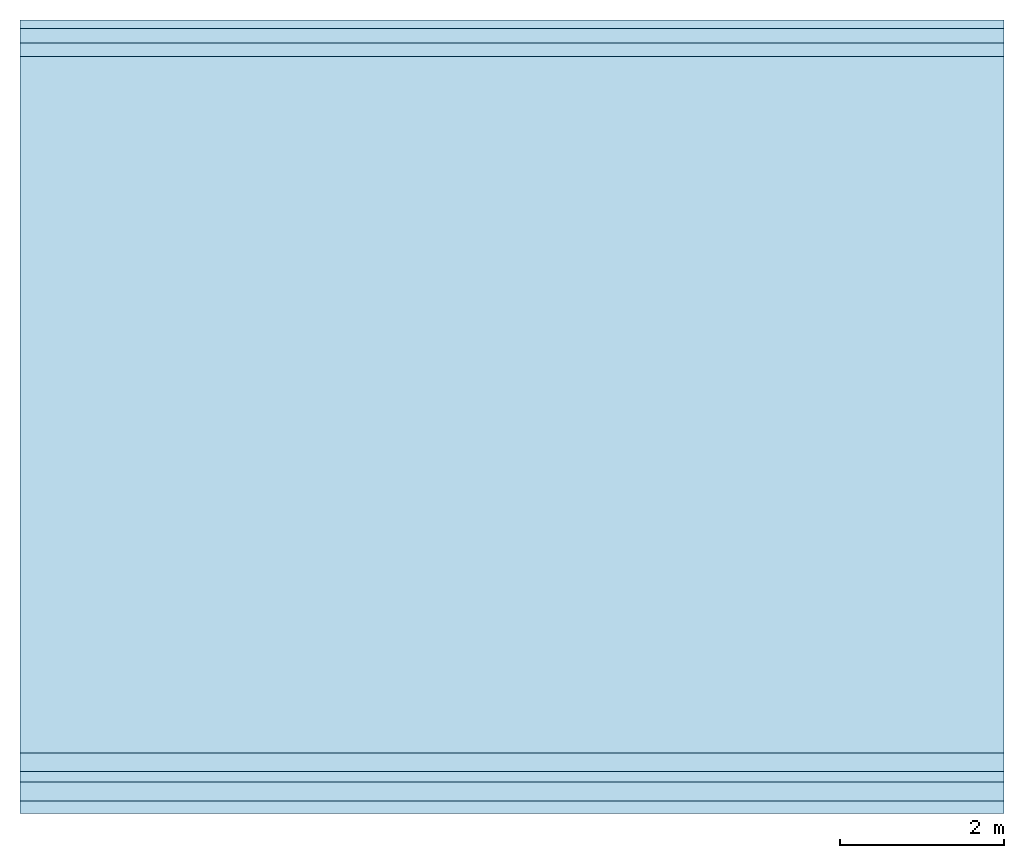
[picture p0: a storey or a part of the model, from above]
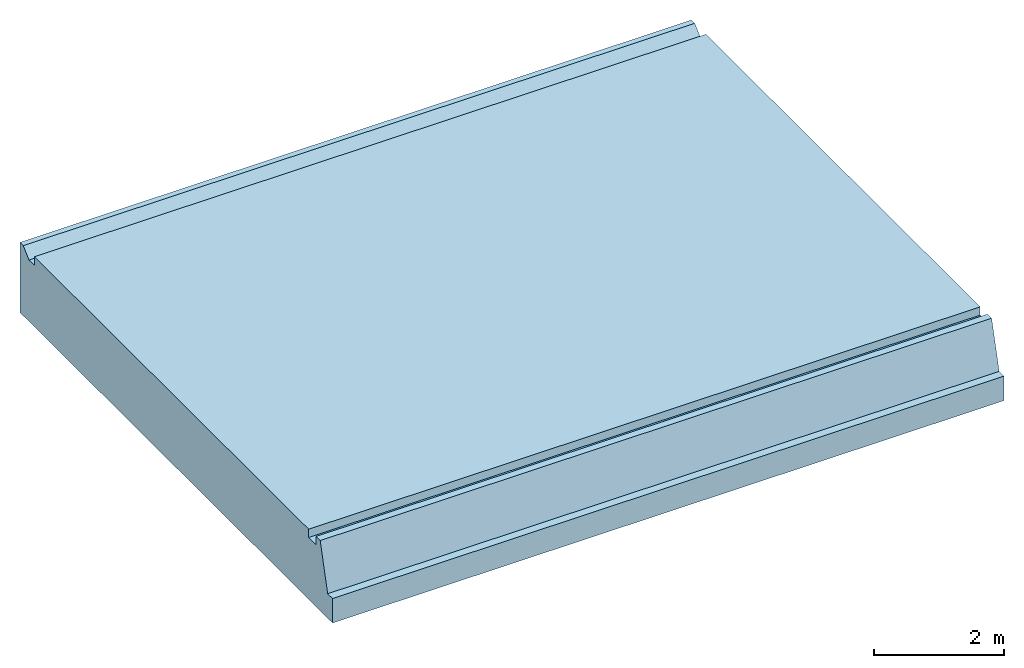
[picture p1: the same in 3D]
Properties of the parts of a building model (IFC2X3)

# File
Description: ViewDefinition [CoordinationView]
File name: VA006-350-202.1 (EDITED).ifc (Edited by Naviate Simple BIM 2022 version 6)
Time: 2026-03-20T14:25:04+01:00
Written by: ODA SDAI 22.12
Made in: Autodesk Revit 23.1.90.15 (ENU) - IFC 23.3.1.0

# IfcProject
LongName: Trondheim Lufthavn Værnes; Phase: TU 2013

# IfcSite, Default
RefLatitude: 59, 54, 57, 601318; RefLongitude: 10, 44, 59, 999999; RefElevation: 0 mm
Identity Data - Workset: Project Info
Text - 01_Modellfil: va006-a-220-1-0001.rvt
Other - RIE, firma: RAMBØLL AS; Project Status: TU 2013; Saksbehandler: MR; Project Address: Skriv adresse her; Category: Project Information; Prosjektansvarlig: TILBUD E203 TETT BYGG; RIV, telefon: +47 7310 6200; RIB, telefon: +47 7289 3750; Project Name: Trondheim Lufthavn Værnes; RIV, firma: MULTICONSULT AS; RIB, firma: NORCONSULT; RIE, telefon: +47 7389 1000
Data - Ideate BIMLink: <?xml version="1.0" encoding="utf-8"?><application version="3"> <links> <link> <name>Casework Types</name> <description></description> <elements>CaseworkTypes</elements> <phase>Fase 2</phase> <phase_filter>None</phase_filter> <properties> <property> <name>Id</name> <lookup_1_type></lookup_1_type> <lookup_1_id></lookup_1_id> <type>BUILT_IN_PARAMETER</type> <id>ID_PARAM</id> </property> <property> <name>Family Name</name> <lookup_1_type></lookup_1_type> <lookup_1_id></lookup_1_id> <type>CALCULATED_PROPERTY</type> <id>FamilyName</id> </property> <property> <name>Type Name</name> <lookup_1_type></lookup_1_type> <lookup_1_id></lookup_1_id> <type>CALCULATED_PROPERTY</type> <id>TypeName</id> </property> </properties> </link> <link> <name>Window Types</name> <description></description> <elements>WindowTypes</elements> <phase>Fase 2</phase> <phase_filter>None</phase_filter> <properties> <property> <name>Id</name> <lookup_1_type></lookup_1_type> <lookup_1_id></lookup_1_id> <type>BUILT_IN_PARAMETER</type> <id>ID_PARAM</id> </property> <property> <name>Family Name</name> <lookup_1_type></lookup_1_type> <lookup_1_id></lookup_1_id> <type>CALCULATED_PROPERTY</type> <id>FamilyName</id> </property> <property> <name>Type Name</name> <lookup_1_type></lookup_1_type> <lookup_1_id></lookup_1_id> <type>CALCULATED_PROPERTY</type> <id>TypeName</id> </property> </properties> </link> <link> <name>Wall Types</name> <description></description> <elements>WallTypes</elements> <phase>Fase 1</phase> <phase_filter>Show Complete</phase_filter> <properties> <property> <name>Id</name> <lookup_1_type></lookup_1_type> <lookup_1_id></lookup_1_id> <type>BUILT_IN_PARAMETER</type> <id>ID_PARAM</id> </property> <property> <name>Family Name</name> <lookup_1_type></lookup_1_type> <lookup_1_id></lookup_1_id> <type>BUILT_IN_PARAMETER</type> <id>SYMBOL_FAMILY_NAME_PARAM</id> </property> <property> <name>Type Name</name> <lookup_1_type></lookup_1_type> <lookup_1_id></lookup_1_id> <type>CALCULATED_PROPERTY</type> <id>TypeName</id> </property> </properties> </link> <link> <name>Structural Framing Types</name> <description></description> <elements>StructuralFramingTypes</elements> <phase>Fase 2</phase> <phase_filter>None</phase_filter> <properties> <property> <name>Id</name> <lookup_1_type></lookup_1_type> <lookup_1_id></lookup_1_id> <type>BUILT_IN_PARAMETER</type> <id>ID_PARAM</id> </property> <property> <name>Family Name</name> <lookup_1_type></lookup_1_type> <lookup_1_id></lookup_1_id> <type>CALCULATED_PROPERTY</type> <id>FamilyName</id> </property> <property> <name>Type Name</name> <lookup_1_type></lookup_1_type> <lookup_1_id></lookup_1_id> <type>CALCULATED_PROPERTY</type> <id>TypeName</id> </property> </properties> </link> <link> <name>Structural Foundation Types</name> <description></description> <elements>StructuralFoundationTypes</elements> <phase>Fase 2</phase> <phase_filter>None</phase_filter> <properties> <property> <name>Id</name> <lookup_1_type></lookup_1_type> <lookup_1_id></lookup_1_id> <type>BUILT_IN_PARAMETER</type> <id>ID_PARAM</id> </property> <property> <name>Family Name</name> <lookup_1_type></lookup_1_type> <lookup_1_id></lookup_1_id> <type>CALCULATED_PROPERTY</type> <id>FamilyName</id> </property> <property> <name>Type Name</name> <lookup_1_type></lookup_1_type> <lookup_1_id></lookup_1_id> <type>CALCULATED_PROPERTY</type> <id>TypeName</id> </property> </properties> </link> <link> <name>Structural Column Types</name> <description></description> <elements>StructuralColumnTypes</elements> <phase>Fase 2</phase> <phase_filter>None</phase_filter> <properties> <property> <name>Id</name> <lookup_1_type></lookup_1_type> <lookup_1_id></lookup_1_id> <type>BUILT_IN_PARAMETER</type> <id>ID_PARAM</id> </property> <property> <name>Family Name</name> <lookup_1_type></lookup_1_type> <lookup_1_id></lookup_1_id> <type>CALCULATED_PROPERTY</type> <id>FamilyName</id> </property> <property> <name>Type Name</name> <lookup_1_type></lookup_1_type> <lookup_1_id></lookup_1_id> <type>CALCULATED_PROPERTY</type> <id>TypeName</id> </property> </properties> </link> <link> <name>Stair Types</name> <description></description> <elements>StairTypes</elements> <phase>Fase 2</phase> <phase_filter>None</phase_filter> <properties> <property> <name>Id</name> <lookup_1_type></lookup_1_type> <lookup_1_id></lookup_1_id> <type>BUILT_IN_PARAMETER</type> <id>ID_PARAM</id> </property> <property> <name>Family Name</name> <lookup_1_type></lookup_1_type> <lookup_1_id></lookup_1_id> <type>BUILT_IN_PARAMETER</type> <id>ALL_MODEL_FAMILY_NAME</id> </property> <property> <name>Type Name</name> <lookup_1_type></lookup_1_type> <lookup_1_id></lookup_1_id> <type>CALCULATED_PROPERTY</type> <id>TypeName</id> </property> </properties> </link> <link> <name>Specialty Equipment Types</name> <description></description> <elements>SpecialtyEquipmentTypes</elements> <phase>Fase 2</phase> <phase_filter>None</phase_filter> <properties> <property> <name>Id</name> <lookup_1_type></lookup_1_type> <lookup_1_id></lookup_1_id> <type>BUILT_IN_PARAMETER</type> <id>ID_PARAM</id> </property> <property> <name>Family Name</name> <lookup_1_type></lookup_1_type> <lookup_1_id></lookup_1_id> <type>CALCULATED_PROPERTY</type> <id>FamilyName</id> </property> <property> <name>Type Name</name> <lookup_1_type></lookup_1_type> <lookup_1_id></lookup_1_id> <type>CALCULATED_PROPERTY</type> <id>TypeName</id> </property> </properties> </link> <link> <name>Roof Types</name> <description></description> <elements>RoofTypes</elements> <phase>Fase 2</phase> <phase_filter>None</phase_filter> <properties> <property> <name>Id</name> <lookup_1_type></lookup_1_type> <lookup_1_id></lookup_1_id> <type>BUILT_IN_PARAMETER</type> <id>ID_PARAM</id> </property> <property> <name>Family Name</name> <lookup_1_type></lookup_1_type> <lookup_1_id></lookup_1_id> <type>BUILT_IN_PARAMETER</type> <id>ALL_MODEL_FAMILY_NAME</id> </property> <property> <name>Type Name</name> <lookup_1_type></lookup_1_type> <lookup_1_id></lookup_1_id> <type>CALCULATED_PROPERTY</type> <id>TypeName</id> </property> </properties> </link> <link> <name>Ramp Types</name> <description></description> <elements>RampTypes</elements> <phase>Fase 2</phase> <phase_filter>None</phase_filter> <properties> <property> <name>Id</name> <lookup_1_type></lookup_1_type> <lookup_1_id></lookup_1_id> <type>BUILT_IN_PARAMETER</type> <id>ID_PARAM</id> </property> <property> <name>Family Name</name> <lookup_1_type></lookup_1_type> <lookup_1_id></lookup_1_id> <type>BUILT_IN_PARAMETER</type> <id>ALL_MODEL_FAMILY_NAME</id> </property> <property> <name>Type Name</name> <lookup_1_type></lookup_1_type> <lookup_1_id></lookup_1_id> <type>CALCULATED_PROPERTY</type> <id>TypeName</id> </property> </properties> </link> <link> <name>Railing Types</name> <description></description> <elements>RailingTypes</elements> <phase>Fase 2</phase> <phase_filter>None</phase_filter> <properties> <property> <name>Id</name> <lookup_1_type></lookup_1_type> <lookup_1_id></lookup_1_id> <type>BUILT_IN_PARAMETER</type> <id>ID_PARAM</id> </property> <property> <name>Family Name</name> <lookup_1_type></lookup_1_type> <lookup_1_id></lookup_1_id> <type>BUILT_IN_PARAMETER</type> <id>ALL_MODEL_FAMILY_NAME</id> </property> <property> <name>Type Name</name> <lookup_1_type></lookup_1_type> <lookup_1_id></lookup_1_id> <type>CALCULATED_PROPERTY</type> <id>TypeName</id> </property> </properties> </link> <link> <name>Profile Types</name> <description></description> <elements>ProfileTypes</elements> <phase>Fase 2</phase> <phase_filter>None</phase_filter> <properties> <property> <name>Id</name> <lookup_1_type></lookup_1_type> <lookup_1_id></lookup_1_id> <type>BUILT_IN_PARAMETER</type> <id>ID_PARAM</id> </property> <property> <name>Family Name</name> <lookup_1_type></lookup_1_type> <lookup_1_id></lookup_1_id> <type>BUILT_IN_PARAMETER</type> <id>ALL_MODEL_FAMILY_NAME</id> </property> <property> <name>Type Name</name> <lookup_1_type></lookup_1_type> <lookup_1_id></lookup_1_id> <type>CALCULATED_PROPERTY</type> <id>TypeName</id> </property> </properties> </link> <link> <name>Plumbing Fixture Types</name> <description></description> <elements>PlumbingFixtureTypes</elements> <phase>Fase 2</phase> <phase_filter>None</phase_filter> <properties> <property> <name>Id</name> <lookup_1_type></lookup_1_type> <lookup_1_id></lookup_1_id> <type>BUILT_IN_PARAMETER</type> <id>ID_PARAM</id> </property> <property> <name>Family Name</name> <lookup_1_type></lookup_1_type> <lookup_1_id></lookup_1_id> <type>CALCULATED_PROPERTY</type> <id>FamilyName</id> </property> <property> <name>Type Name</name> <lookup_1_type></lookup_1_type> <lookup_1_id></lookup_1_id> <type>CALCULATED_PROPERTY</type> <id>TypeName</id> </property> </properties> </link> <link> <name>Mechanical Equipment Types</name> <description></description> <elements>MechanicalEquipmentTypes</elements> <phase>Fase 2</phase> <phase_filter>None</phase_filter> <properties> <property> <name>Id</name> <lookup_1_type></lookup_1_type> <lookup_1_id></lookup_1_id> <type>BUILT_IN_PARAMETER</type> <id>ID_PARAM</id> </property> <property> <name>Family Name</name> <lookup_1_type></lookup_1_type> <lookup_1_id></lookup_1_id> <type>CALCULATED_PROPERTY</type> <id>FamilyName</id> </property> <property> <name>Type Name</name> <lookup_1_type></lookup_1_type> <lookup_1_id></lookup_1_id> <type>CALCULATED_PROPERTY</type> <id>TypeName</id> </property> </properties> </link> <link> <name>Mass Types</name> <description></description> <elements>MassTypes</elements> <phase>Fase 2</phase> <phase_filter>None</phase_filter> <properties> <property> <name>Id</name> <lookup_1_type></lookup_1_type> <lookup_1_id></lookup_1_id> <type>BUILT_IN_PARAMETER</type> <id>ID_PARAM</id> </property> <property> <name>Family Name</name> <lookup_1_type></lookup_1_type> <lookup_1_id></lookup_1_id> <type>CALCULATED_PROPERTY</type> <id>FamilyName</id> </property> <property> <name>Type Name</name> <lookup_1_type></lookup_1_type> <lookup_1_id></lookup_1_id> <type>CALCULATED_PROPERTY</type> <id>TypeName</id> </property> </properties> </link> <link> <name>Generic Model Types</name> <description></description> <elements>GenericModelTypes</elements> <phase>Fase 2</phase> <phase_filter>None</phase_filter> <properties> <property> <name>Id</name> <lookup_1_type></lookup_1_type> <lookup_1_id></lookup_1_id> <type>BUILT_IN_PARAMETER</type> <id>ID_PARAM</id> </property> <property> <name>Family Name</name> <lookup_1_type></lookup_1_type> <lookup_1_id></lookup_1_id> <type>CALCULATED_PROPERTY</type> <id>FamilyName</id> </property> <property> <name>Type Name</name> <lookup_1_type></lookup_1_type> <lookup_1_id></lookup_1_id> <type>CALCULATED_PROPERTY</type> <id>TypeName</id> </property> </properties> </link> <link> <name>Column Types</name> <description></description> <elements>ColumnTypes</elements> <phase>Fase 2</phase> <phase_filter>None</phase_filter> <properties> <property> <name>Id</name> <lookup_1_type></lookup_1_type> <lookup_1_id></lookup_1_id> <type>BUILT_IN_PARAMETER</type> <id>ID_PARAM</id> </property> <property> <name>Family Name</name> <lookup_1_type></lookup_1_type> <lookup_1_id></lookup_1_id> <type>CALCULATED_PROPERTY</type> <id>FamilyName</id> </property> <property> <name>Type Name</name> <lookup_1_type></lookup_1_type> <lookup_1_id></lookup_1_id> <type>CALCULATED_PROPERTY</type> <id>TypeName</id> </property> </properties> </link> <link> <name>Columns</name> <description></description> <elements>ColumnInstances</elements> <phase>Fase 2</phase> <phase_filter>None</phase_filter> <properties> <property> <name>Id</name> <lookup_1_type></lookup_1_type> <lookup_1_id></lookup_1_id> <type>BUILT_IN_PARAMETER</type> <id>ID_PARAM</id> </property> </properties> </link> <link> <name>Door Types</name> <description></description> <elements>DoorTypes</elements> <phase>Fase 2</phase> <phase_filter>None</phase_filter> <properties> <property> <name>Id</name> <lookup_1_type></lookup_1_type> <lookup_1_id></lookup_1_id> <type>BUILT_IN_PARAMETER</type> <id>ID_PARAM</id> </property> <property> <name>Family Name</name> <lookup_1_type></lookup_1_type> <lookup_1_id></lookup_1_id> <type>CALCULATED_PROPERTY</type> <id>FamilyName</id> </property> <property> <name>Type Name</name> <lookup_1_type></lookup_1_type> <lookup_1_id></lookup_1_id> <type>CALCULATED_PROPERTY</type> <id>TypeName</id> </property> </properties> </link> <link> <name>Door Types 2</name> <description></description> <elements>DoorTypes</elements> <phase>Fase 1</phase> <phase_filter>Show Complete</phase_filter> <properties> <property> <name>Id</name> <lookup_1_type></lookup_1_type> <lookup_1_id></lookup_1_id> <type>BUILT_IN_PARAMETER</type> <id>ID_PARAM</id> </property> <property> <name>Family Name</name> <lookup_1_type></lookup_1_type> <lookup_1_id></lookup_1_id> <type>CALCULATED_PROPERTY</type> <id>FamilyName</id> </property> <property> <name>Type Name</name> <lookup_1_type></lookup_1_type> <lookup_1_id></lookup_1_id> <type>CALCULATED_PROPERTY</type> <id>TypeName</id> </property> </properties> </link> <link> <name>Ceiling Types</name> <description></description> <elements>CeilingTypes</elements> <phase>Fase 2</phase> <phase_filter>None</phase_filter> <properties> <property> <name>Id</name> <lookup_1_type></lookup_1_type> <lookup_1_id></lookup_1_id> <type>BUILT_IN_PARAMETER</type> <id>ID_PARAM</id> </property> <property> <name>Family Name</name> <lookup_1_type></lookup_1_type> <lookup_1_id></lookup_1_id> <type>BUILT_IN_PARAMETER</type> <id>ALL_MODEL_FAMILY_NAME</id> </property> <property> <name>Type Name</name> <lookup_1_type></lookup_1_type> <lookup_1_id></lookup_1_id> <type>CALCULATED_PROPERTY</type> <id>TypeName</id> </property> </properties> </link> <link> <name>Ceilings</name> <description></description> <elements>CeilingInstances</elements> <phase>Fase 2</phase> <phase_filter>None</phase_filter> <properties> <property> <name>Id</name> <lookup_1_type></lookup_1_type> <lookup_1_id></lookup_1_id> <type>BUILT_IN_PARAMETER</type> <id>ID_PARAM</id> </property> <property> <name>Family Name</name> <lookup_1_type>BUILT_IN_PARAMETER</lookup_1_type> <lookup_1_id>SYMBOL_ID_PARAM</lookup_1_id> <type>BUILT_IN_PARAMETER</type> <id>ALL_MODEL_FAMILY_NAME</id> </property> <property> <name>Type Name</name> <lookup_1_type>BUILT_IN_PARAMETER</lookup_1_type> <lookup_1_id>SYMBOL_ID_PARAM</lookup_1_id> <type>CALCULATED_PROPERTY</type> <id>TypeName</id> </property> </properties> </link> <link> <name>Furniture Types</name> <description></description> <elements>FurnitureTypes</elements> <phase>Fase 2</phase> <phase_filter>None</phase_filter> <properties> <property> <name>Id</name> <lookup_1_type></lookup_1_type> <lookup_1_id></lookup_1_id> <type>BUILT_IN_PARAMETER</type> <id>ID_PARAM</id> </property> <property> <name>Family Name</name> <lookup_1_type></lookup_1_type> <lookup_1_id></lookup_1_id> <type>CALCULATED_PROPERTY</type> <id>FamilyName</id> </property> <property> <name>Type Name</name> <lookup_1_type></lookup_1_type> <lookup_1_id></lookup_1_id> <type>CALCULATED_PROPERTY</type> <id>TypeName</id> </property> </properties> </link> <link> <name>Furniture System Types</name> <description></description> <elements>FurnitureSystemTypes</elements> <phase>Fase 2</phase> <phase_filter>None</phase_filter> <properties> <property> <name>Id</name> <lookup_1_type></lookup_1_type> <lookup_1_id></lookup_1_id> <type>BUILT_IN_PARAMETER</type> <id>ID_PARAM</id> </property> <property> <name>Family Name</name> <lookup_1_type></lookup_1_type> <lookup_1_id></lookup_1_id> <type>CALCULATED_PROPERTY</type> <id>FamilyName</id> </property> <property> <name>Type Name</name> <lookup_1_type></lookup_1_type> <lookup_1_id></lookup_1_id> <type>CALCULATED_PROPERTY</type> <id>TypeName</id> </property> </properties> </link> <link> <name>Sheets</name> <description></description> <elements>Sheets</elements> <phase>Fase 1</phase> <phase_filter>None</phase_filter> <properties> <property> <name>Id</name> <lookup_1_type></lookup_1_type> <lookup_1_id></lookup_1_id> <type>BUILT_IN_PARAMETER</type> <id>ID_PARAM</id> </property> </properties> </link> <link> <name>Walls</name> <description></description> <elements>WallInstances</elements> <phase>Fase 2</phase> <phase_filter>None</phase_filter> <properties> <property> <name>Id</name> <lookup_1_type></lookup_1_type> <lookup_1_id></lookup_1_id> <type>BUILT_IN_PARAMETER</type> <id>ID_PARAM</id> </property> </properties> </link> <link> <name>Wall types all official names</name> <description></description> <elements>WallTypes</elements> <phase>Fase 1</phase> <phase_filter>None</phase_filter> <properties> <property> <name>Id</name> <lookup_1_type></lookup_1_type> <lookup_1_id></lookup_1_id> <type>BUILT_IN_PARAMETER</type> <id>ID_PARAM</id> </property> <property> <name>Family Name</name> <lookup_1_type></lookup_1_type> <lookup_1_id></lookup_1_id> <type>BUILT_IN_PARAMETER</type> <id>ALL_MODEL_FAMILY_NAME</id> </property> <property> <name>Type Name</name> <lookup_1_type></lookup_1_type> <lookup_1_id></lookup_1_id> <type>CALCULATED_PROPERTY</type> <id>TypeName</id> </property> </properties> </link> <link> <name>test</name> <description></description> <elements>WallTypes</elements> <phase>Fase 1</phase> <phase_filter>None</phase_filter> <properties> <property> <name>Id</name> <lookup_1_type></lookup_1_type> <lookup_1_id></lookup_1_id> <type>BUILT_IN_PARAMETER</type> <id>ID_PARAM</id> </property> <property> <name>Family Name</name> <lookup_1_type></lookup_1_type> <lookup_1_id></lookup_1_id> <type>BUILT_IN_PARAMETER</type> <id>ALL_MODEL_FAMILY_NAME</id> </property> <property> <name>Type Name</name> <lookup_1_type></lookup_1_type> <lookup_1_id></lookup_1_id> <type>CALCULATED_PROPERTY</type> <id>TypeName</id> </property> </properties> </link> </links></application>

# IfcBuilding
Pset_BuildingCommon - NumberOfStoreys: 6
Identity Data - Workset: Project Info
Text - 01_Modellfil: va006-a-220-1-0001.rvt
Data - Ideate BIMLink: <?xml version="1.0" encoding="utf-8"?><application version="3"> <links> <link> <name>Casework Types</name> <description></description> <elements>CaseworkTypes</elements> <phase>Fase 2</phase> <phase_filter>None</phase_filter> <properties> <property> <name>Id</name> <lookup_1_type></lookup_1_type> <lookup_1_id></lookup_1_id> <type>BUILT_IN_PARAMETER</type> <id>ID_PARAM</id> </property> <property> <name>Family Name</name> <lookup_1_type></lookup_1_type> <lookup_1_id></lookup_1_id> <type>CALCULATED_PROPERTY</type> <id>FamilyName</id> </property> <property> <name>Type Name</name> <lookup_1_type></lookup_1_type> <lookup_1_id></lookup_1_id> <type>CALCULATED_PROPERTY</type> <id>TypeName</id> </property> </properties> </link> <link> <name>Window Types</name> <description></description> <elements>WindowTypes</elements> <phase>Fase 2</phase> <phase_filter>None</phase_filter> <properties> <property> <name>Id</name> <lookup_1_type></lookup_1_type> <lookup_1_id></lookup_1_id> <type>BUILT_IN_PARAMETER</type> <id>ID_PARAM</id> </property> <property> <name>Family Name</name> <lookup_1_type></lookup_1_type> <lookup_1_id></lookup_1_id> <type>CALCULATED_PROPERTY</type> <id>FamilyName</id> </property> <property> <name>Type Name</name> <lookup_1_type></lookup_1_type> <lookup_1_id></lookup_1_id> <type>CALCULATED_PROPERTY</type> <id>TypeName</id> </property> </properties> </link> <link> <name>Wall Types</name> <description></description> <elements>WallTypes</elements> <phase>Fase 1</phase> <phase_filter>Show Complete</phase_filter> <properties> <property> <name>Id</name> <lookup_1_type></lookup_1_type> <lookup_1_id></lookup_1_id> <type>BUILT_IN_PARAMETER</type> <id>ID_PARAM</id> </property> <property> <name>Family Name</name> <lookup_1_type></lookup_1_type> <lookup_1_id></lookup_1_id> <type>BUILT_IN_PARAMETER</type> <id>SYMBOL_FAMILY_NAME_PARAM</id> </property> <property> <name>Type Name</name> <lookup_1_type></lookup_1_type> <lookup_1_id></lookup_1_id> <type>CALCULATED_PROPERTY</type> <id>TypeName</id> </property> </properties> </link> <link> <name>Structural Framing Types</name> <description></description> <elements>StructuralFramingTypes</elements> <phase>Fase 2</phase> <phase_filter>None</phase_filter> <properties> <property> <name>Id</name> <lookup_1_type></lookup_1_type> <lookup_1_id></lookup_1_id> <type>BUILT_IN_PARAMETER</type> <id>ID_PARAM</id> </property> <property> <name>Family Name</name> <lookup_1_type></lookup_1_type> <lookup_1_id></lookup_1_id> <type>CALCULATED_PROPERTY</type> <id>FamilyName</id> </property> <property> <name>Type Name</name> <lookup_1_type></lookup_1_type> <lookup_1_id></lookup_1_id> <type>CALCULATED_PROPERTY</type> <id>TypeName</id> </property> </properties> </link> <link> <name>Structural Foundation Types</name> <description></description> <elements>StructuralFoundationTypes</elements> <phase>Fase 2</phase> <phase_filter>None</phase_filter> <properties> <property> <name>Id</name> <lookup_1_type></lookup_1_type> <lookup_1_id></lookup_1_id> <type>BUILT_IN_PARAMETER</type> <id>ID_PARAM</id> </property> <property> <name>Family Name</name> <lookup_1_type></lookup_1_type> <lookup_1_id></lookup_1_id> <type>CALCULATED_PROPERTY</type> <id>FamilyName</id> </property> <property> <name>Type Name</name> <lookup_1_type></lookup_1_type> <lookup_1_id></lookup_1_id> <type>CALCULATED_PROPERTY</type> <id>TypeName</id> </property> </properties> </link> <link> <name>Structural Column Types</name> <description></description> <elements>StructuralColumnTypes</elements> <phase>Fase 2</phase> <phase_filter>None</phase_filter> <properties> <property> <name>Id</name> <lookup_1_type></lookup_1_type> <lookup_1_id></lookup_1_id> <type>BUILT_IN_PARAMETER</type> <id>ID_PARAM</id> </property> <property> <name>Family Name</name> <lookup_1_type></lookup_1_type> <lookup_1_id></lookup_1_id> <type>CALCULATED_PROPERTY</type> <id>FamilyName</id> </property> <property> <name>Type Name</name> <lookup_1_type></lookup_1_type> <lookup_1_id></lookup_1_id> <type>CALCULATED_PROPERTY</type> <id>TypeName</id> </property> </properties> </link> <link> <name>Stair Types</name> <description></description> <elements>StairTypes</elements> <phase>Fase 2</phase> <phase_filter>None</phase_filter> <properties> <property> <name>Id</name> <lookup_1_type></lookup_1_type> <lookup_1_id></lookup_1_id> <type>BUILT_IN_PARAMETER</type> <id>ID_PARAM</id> </property> <property> <name>Family Name</name> <lookup_1_type></lookup_1_type> <lookup_1_id></lookup_1_id> <type>BUILT_IN_PARAMETER</type> <id>ALL_MODEL_FAMILY_NAME</id> </property> <property> <name>Type Name</name> <lookup_1_type></lookup_1_type> <lookup_1_id></lookup_1_id> <type>CALCULATED_PROPERTY</type> <id>TypeName</id> </property> </properties> </link> <link> <name>Specialty Equipment Types</name> <description></description> <elements>SpecialtyEquipmentTypes</elements> <phase>Fase 2</phase> <phase_filter>None</phase_filter> <properties> <property> <name>Id</name> <lookup_1_type></lookup_1_type> <lookup_1_id></lookup_1_id> <type>BUILT_IN_PARAMETER</type> <id>ID_PARAM</id> </property> <property> <name>Family Name</name> <lookup_1_type></lookup_1_type> <lookup_1_id></lookup_1_id> <type>CALCULATED_PROPERTY</type> <id>FamilyName</id> </property> <property> <name>Type Name</name> <lookup_1_type></lookup_1_type> <lookup_1_id></lookup_1_id> <type>CALCULATED_PROPERTY</type> <id>TypeName</id> </property> </properties> </link> <link> <name>Roof Types</name> <description></description> <elements>RoofTypes</elements> <phase>Fase 2</phase> <phase_filter>None</phase_filter> <properties> <property> <name>Id</name> <lookup_1_type></lookup_1_type> <lookup_1_id></lookup_1_id> <type>BUILT_IN_PARAMETER</type> <id>ID_PARAM</id> </property> <property> <name>Family Name</name> <lookup_1_type></lookup_1_type> <lookup_1_id></lookup_1_id> <type>BUILT_IN_PARAMETER</type> <id>ALL_MODEL_FAMILY_NAME</id> </property> <property> <name>Type Name</name> <lookup_1_type></lookup_1_type> <lookup_1_id></lookup_1_id> <type>CALCULATED_PROPERTY</type> <id>TypeName</id> </property> </properties> </link> <link> <name>Ramp Types</name> <description></description> <elements>RampTypes</elements> <phase>Fase 2</phase> <phase_filter>None</phase_filter> <properties> <property> <name>Id</name> <lookup_1_type></lookup_1_type> <lookup_1_id></lookup_1_id> <type>BUILT_IN_PARAMETER</type> <id>ID_PARAM</id> </property> <property> <name>Family Name</name> <lookup_1_type></lookup_1_type> <lookup_1_id></lookup_1_id> <type>BUILT_IN_PARAMETER</type> <id>ALL_MODEL_FAMILY_NAME</id> </property> <property> <name>Type Name</name> <lookup_1_type></lookup_1_type> <lookup_1_id></lookup_1_id> <type>CALCULATED_PROPERTY</type> <id>TypeName</id> </property> </properties> </link> <link> <name>Railing Types</name> <description></description> <elements>RailingTypes</elements> <phase>Fase 2</phase> <phase_filter>None</phase_filter> <properties> <property> <name>Id</name> <lookup_1_type></lookup_1_type> <lookup_1_id></lookup_1_id> <type>BUILT_IN_PARAMETER</type> <id>ID_PARAM</id> </property> <property> <name>Family Name</name> <lookup_1_type></lookup_1_type> <lookup_1_id></lookup_1_id> <type>BUILT_IN_PARAMETER</type> <id>ALL_MODEL_FAMILY_NAME</id> </property> <property> <name>Type Name</name> <lookup_1_type></lookup_1_type> <lookup_1_id></lookup_1_id> <type>CALCULATED_PROPERTY</type> <id>TypeName</id> </property> </properties> </link> <link> <name>Profile Types</name> <description></description> <elements>ProfileTypes</elements> <phase>Fase 2</phase> <phase_filter>None</phase_filter> <properties> <property> <name>Id</name> <lookup_1_type></lookup_1_type> <lookup_1_id></lookup_1_id> <type>BUILT_IN_PARAMETER</type> <id>ID_PARAM</id> </property> <property> <name>Family Name</name> <lookup_1_type></lookup_1_type> <lookup_1_id></lookup_1_id> <type>BUILT_IN_PARAMETER</type> <id>ALL_MODEL_FAMILY_NAME</id> </property> <property> <name>Type Name</name> <lookup_1_type></lookup_1_type> <lookup_1_id></lookup_1_id> <type>CALCULATED_PROPERTY</type> <id>TypeName</id> </property> </properties> </link> <link> <name>Plumbing Fixture Types</name> <description></description> <elements>PlumbingFixtureTypes</elements> <phase>Fase 2</phase> <phase_filter>None</phase_filter> <properties> <property> <name>Id</name> <lookup_1_type></lookup_1_type> <lookup_1_id></lookup_1_id> <type>BUILT_IN_PARAMETER</type> <id>ID_PARAM</id> </property> <property> <name>Family Name</name> <lookup_1_type></lookup_1_type> <lookup_1_id></lookup_1_id> <type>CALCULATED_PROPERTY</type> <id>FamilyName</id> </property> <property> <name>Type Name</name> <lookup_1_type></lookup_1_type> <lookup_1_id></lookup_1_id> <type>CALCULATED_PROPERTY</type> <id>TypeName</id> </property> </properties> </link> <link> <name>Mechanical Equipment Types</name> <description></description> <elements>MechanicalEquipmentTypes</elements> <phase>Fase 2</phase> <phase_filter>None</phase_filter> <properties> <property> <name>Id</name> <lookup_1_type></lookup_1_type> <lookup_1_id></lookup_1_id> <type>BUILT_IN_PARAMETER</type> <id>ID_PARAM</id> </property> <property> <name>Family Name</name> <lookup_1_type></lookup_1_type> <lookup_1_id></lookup_1_id> <type>CALCULATED_PROPERTY</type> <id>FamilyName</id> </property> <property> <name>Type Name</name> <lookup_1_type></lookup_1_type> <lookup_1_id></lookup_1_id> <type>CALCULATED_PROPERTY</type> <id>TypeName</id> </property> </properties> </link> <link> <name>Mass Types</name> <description></description> <elements>MassTypes</elements> <phase>Fase 2</phase> <phase_filter>None</phase_filter> <properties> <property> <name>Id</name> <lookup_1_type></lookup_1_type> <lookup_1_id></lookup_1_id> <type>BUILT_IN_PARAMETER</type> <id>ID_PARAM</id> </property> <property> <name>Family Name</name> <lookup_1_type></lookup_1_type> <lookup_1_id></lookup_1_id> <type>CALCULATED_PROPERTY</type> <id>FamilyName</id> </property> <property> <name>Type Name</name> <lookup_1_type></lookup_1_type> <lookup_1_id></lookup_1_id> <type>CALCULATED_PROPERTY</type> <id>TypeName</id> </property> </properties> </link> <link> <name>Generic Model Types</name> <description></description> <elements>GenericModelTypes</elements> <phase>Fase 2</phase> <phase_filter>None</phase_filter> <properties> <property> <name>Id</name> <lookup_1_type></lookup_1_type> <lookup_1_id></lookup_1_id> <type>BUILT_IN_PARAMETER</type> <id>ID_PARAM</id> </property> <property> <name>Family Name</name> <lookup_1_type></lookup_1_type> <lookup_1_id></lookup_1_id> <type>CALCULATED_PROPERTY</type> <id>FamilyName</id> </property> <property> <name>Type Name</name> <lookup_1_type></lookup_1_type> <lookup_1_id></lookup_1_id> <type>CALCULATED_PROPERTY</type> <id>TypeName</id> </property> </properties> </link> <link> <name>Column Types</name> <description></description> <elements>ColumnTypes</elements> <phase>Fase 2</phase> <phase_filter>None</phase_filter> <properties> <property> <name>Id</name> <lookup_1_type></lookup_1_type> <lookup_1_id></lookup_1_id> <type>BUILT_IN_PARAMETER</type> <id>ID_PARAM</id> </property> <property> <name>Family Name</name> <lookup_1_type></lookup_1_type> <lookup_1_id></lookup_1_id> <type>CALCULATED_PROPERTY</type> <id>FamilyName</id> </property> <property> <name>Type Name</name> <lookup_1_type></lookup_1_type> <lookup_1_id></lookup_1_id> <type>CALCULATED_PROPERTY</type> <id>TypeName</id> </property> </properties> </link> <link> <name>Columns</name> <description></description> <elements>ColumnInstances</elements> <phase>Fase 2</phase> <phase_filter>None</phase_filter> <properties> <property> <name>Id</name> <lookup_1_type></lookup_1_type> <lookup_1_id></lookup_1_id> <type>BUILT_IN_PARAMETER</type> <id>ID_PARAM</id> </property> </properties> </link> <link> <name>Door Types</name> <description></description> <elements>DoorTypes</elements> <phase>Fase 2</phase> <phase_filter>None</phase_filter> <properties> <property> <name>Id</name> <lookup_1_type></lookup_1_type> <lookup_1_id></lookup_1_id> <type>BUILT_IN_PARAMETER</type> <id>ID_PARAM</id> </property> <property> <name>Family Name</name> <lookup_1_type></lookup_1_type> <lookup_1_id></lookup_1_id> <type>CALCULATED_PROPERTY</type> <id>FamilyName</id> </property> <property> <name>Type Name</name> <lookup_1_type></lookup_1_type> <lookup_1_id></lookup_1_id> <type>CALCULATED_PROPERTY</type> <id>TypeName</id> </property> </properties> </link> <link> <name>Door Types 2</name> <description></description> <elements>DoorTypes</elements> <phase>Fase 1</phase> <phase_filter>Show Complete</phase_filter> <properties> <property> <name>Id</name> <lookup_1_type></lookup_1_type> <lookup_1_id></lookup_1_id> <type>BUILT_IN_PARAMETER</type> <id>ID_PARAM</id> </property> <property> <name>Family Name</name> <lookup_1_type></lookup_1_type> <lookup_1_id></lookup_1_id> <type>CALCULATED_PROPERTY</type> <id>FamilyName</id> </property> <property> <name>Type Name</name> <lookup_1_type></lookup_1_type> <lookup_1_id></lookup_1_id> <type>CALCULATED_PROPERTY</type> <id>TypeName</id> </property> </properties> </link> <link> <name>Ceiling Types</name> <description></description> <elements>CeilingTypes</elements> <phase>Fase 2</phase> <phase_filter>None</phase_filter> <properties> <property> <name>Id</name> <lookup_1_type></lookup_1_type> <lookup_1_id></lookup_1_id> <type>BUILT_IN_PARAMETER</type> <id>ID_PARAM</id> </property> <property> <name>Family Name</name> <lookup_1_type></lookup_1_type> <lookup_1_id></lookup_1_id> <type>BUILT_IN_PARAMETER</type> <id>ALL_MODEL_FAMILY_NAME</id> </property> <property> <name>Type Name</name> <lookup_1_type></lookup_1_type> <lookup_1_id></lookup_1_id> <type>CALCULATED_PROPERTY</type> <id>TypeName</id> </property> </properties> </link> <link> <name>Ceilings</name> <description></description> <elements>CeilingInstances</elements> <phase>Fase 2</phase> <phase_filter>None</phase_filter> <properties> <property> <name>Id</name> <lookup_1_type></lookup_1_type> <lookup_1_id></lookup_1_id> <type>BUILT_IN_PARAMETER</type> <id>ID_PARAM</id> </property> <property> <name>Family Name</name> <lookup_1_type>BUILT_IN_PARAMETER</lookup_1_type> <lookup_1_id>SYMBOL_ID_PARAM</lookup_1_id> <type>BUILT_IN_PARAMETER</type> <id>ALL_MODEL_FAMILY_NAME</id> </property> <property> <name>Type Name</name> <lookup_1_type>BUILT_IN_PARAMETER</lookup_1_type> <lookup_1_id>SYMBOL_ID_PARAM</lookup_1_id> <type>CALCULATED_PROPERTY</type> <id>TypeName</id> </property> </properties> </link> <link> <name>Furniture Types</name> <description></description> <elements>FurnitureTypes</elements> <phase>Fase 2</phase> <phase_filter>None</phase_filter> <properties> <property> <name>Id</name> <lookup_1_type></lookup_1_type> <lookup_1_id></lookup_1_id> <type>BUILT_IN_PARAMETER</type> <id>ID_PARAM</id> </property> <property> <name>Family Name</name> <lookup_1_type></lookup_1_type> <lookup_1_id></lookup_1_id> <type>CALCULATED_PROPERTY</type> <id>FamilyName</id> </property> <property> <name>Type Name</name> <lookup_1_type></lookup_1_type> <lookup_1_id></lookup_1_id> <type>CALCULATED_PROPERTY</type> <id>TypeName</id> </property> </properties> </link> <link> <name>Furniture System Types</name> <description></description> <elements>FurnitureSystemTypes</elements> <phase>Fase 2</phase> <phase_filter>None</phase_filter> <properties> <property> <name>Id</name> <lookup_1_type></lookup_1_type> <lookup_1_id></lookup_1_id> <type>BUILT_IN_PARAMETER</type> <id>ID_PARAM</id> </property> <property> <name>Family Name</name> <lookup_1_type></lookup_1_type> <lookup_1_id></lookup_1_id> <type>CALCULATED_PROPERTY</type> <id>FamilyName</id> </property> <property> <name>Type Name</name> <lookup_1_type></lookup_1_type> <lookup_1_id></lookup_1_id> <type>CALCULATED_PROPERTY</type> <id>TypeName</id> </property> </properties> </link> <link> <name>Sheets</name> <description></description> <elements>Sheets</elements> <phase>Fase 1</phase> <phase_filter>None</phase_filter> <properties> <property> <name>Id</name> <lookup_1_type></lookup_1_type> <lookup_1_id></lookup_1_id> <type>BUILT_IN_PARAMETER</type> <id>ID_PARAM</id> </property> </properties> </link> <link> <name>Walls</name> <description></description> <elements>WallInstances</elements> <phase>Fase 2</phase> <phase_filter>None</phase_filter> <properties> <property> <name>Id</name> <lookup_1_type></lookup_1_type> <lookup_1_id></lookup_1_id> <type>BUILT_IN_PARAMETER</type> <id>ID_PARAM</id> </property> </properties> </link> <link> <name>Wall types all official names</name> <description></description> <elements>WallTypes</elements> <phase>Fase 1</phase> <phase_filter>None</phase_filter> <properties> <property> <name>Id</name> <lookup_1_type></lookup_1_type> <lookup_1_id></lookup_1_id> <type>BUILT_IN_PARAMETER</type> <id>ID_PARAM</id> </property> <property> <name>Family Name</name> <lookup_1_type></lookup_1_type> <lookup_1_id></lookup_1_id> <type>BUILT_IN_PARAMETER</type> <id>ALL_MODEL_FAMILY_NAME</id> </property> <property> <name>Type Name</name> <lookup_1_type></lookup_1_type> <lookup_1_id></lookup_1_id> <type>CALCULATED_PROPERTY</type> <id>TypeName</id> </property> </properties> </link> <link> <name>test</name> <description></description> <elements>WallTypes</elements> <phase>Fase 1</phase> <phase_filter>None</phase_filter> <properties> <property> <name>Id</name> <lookup_1_type></lookup_1_type> <lookup_1_id></lookup_1_id> <type>BUILT_IN_PARAMETER</type> <id>ID_PARAM</id> </property> <property> <name>Family Name</name> <lookup_1_type></lookup_1_type> <lookup_1_id></lookup_1_id> <type>BUILT_IN_PARAMETER</type> <id>ALL_MODEL_FAMILY_NAME</id> </property> <property> <name>Type Name</name> <lookup_1_type></lookup_1_type> <lookup_1_id></lookup_1_id> <type>CALCULATED_PROPERTY</type> <id>TypeName</id> </property> </properties> </link> </links></application>
Other - RIE, firma: RAMBØLL AS; Project Status: TU 2013; Saksbehandler: MR; Project Address: Skriv adresse her; Category: Project Information; Prosjektansvarlig: TILBUD E203 TETT BYGG; RIV, telefon: +47 7310 6200; RIB, telefon: +47 7289 3750; Project Name: Trondheim Lufthavn Værnes; RIV, firma: MULTICONSULT AS; RIB, firma: NORCONSULT; RIE, telefon: +47 7389 1000

# IfcBuildingStorey: Level:TA, XX - C +15,37 TA E2
LongName: XX - C +15,37 TA E2; Elevation: 15370 mm
Other - Family and Type: Level: TA; Type Id: 7724934; Type: TA; Category: Levels; Family: Level
Identity Data(Type) - Workset: Level Types; Type Name: TA
Constraints - Elevation: 15370 mm
Graphics(Type) - Symbol: NSW Kote - Triangel med kote, ISO 2,5 mm (fault, do not use -DC) : NSW Kote - Triangel med kote, ISO 2,5 mm; Line Pattern: Centre; Color: 0; Symbol at End 1 Default: yes; Symbol at End 2 Default: no; Line Weight: 4
Pset_AirSideSystemInformation - Name: XX - C +15,37 TA E2; sets with these values: 2
Identity Data - Structural: no; Building Story: yes; Name: XX - C +15,37 TA E2; Workset: Shared Levels and Grids
Constraints(Type) - Elevation Base: Project Base Point
Dimensions - Computation Height: 1200 mm
Other(Type) - Category: Levels; Family Name: Level

# IfcBuildingStorey: Level:TB, XX - C +18,10 TB Tak 1
LongName: XX - C +18,10 TB Tak 1; Elevation: 18100 mm
Identity Data - Structural: no; Building Story: yes; Name: XX - C +18,10 TB Tak 1; Workset: Shared Levels and Grids
Constraints - Elevation: 18100 mm
Graphics(Type) - Symbol: NSW Kote - Triangel med kote, ISO 2,5 mm (fault, do not use -DC) : NSW Kote - Triangel med kote, ISO 2,5 mm; Line Pattern: Centre; Color: 0; Symbol at End 1 Default: yes; Symbol at End 2 Default: no; Line Weight: 4
Identity Data(Type) - Workset: Level Types; Type Name: TB
Other - Family and Type: Level: TB; Type: TB; Type Id: 7617874; Category: Levels; Family: Level
Pset_ProductRequirements - Name: XX - C +18,10 TB Tak 1; sets with these values: 2
Constraints(Type) - Elevation Base: Project Base Point
Other(Type) - Category: Levels; Family Name: Level
Dimensions - Computation Height: 0 mm

# IfcBuildingElementProxy: V_TA Stål Facade Columns Type 4:V_TA Stål Facade Columns (3)
In: XX - C +15,37 TA E2
Type - Material: <Unnamed>
Type - Other - Category: Structural Framing; Family Name: V_TA Stål Facade Columns Type 4
Type - Constraints - Default Elevation: 1219.2 mm
Type - Identity Data - Type Name: V_TA Stål Facade Columns; Workset: Family : Structural Framing : V_TA Stål Facade Columns Type 4
Type - Structural - Section Shape: 0
Phasing - Phase Created: Som Bygget
ePset_LocationTool - Splitting: RESULT
Constraints - Host: System Panel : Glazed-generic; Schedule Level: XX - C +15,37 TA E2; Level: XX - C +15,37 TA E2
Identity Data - TA Workset: yes; Workset: XTA Terminal A
Structural - Rebar Cover - Bottom Face: Rebar Cover 1 <25 mm>; Rebar Cover - Other Faces: Rebar Cover 1 <25 mm>; Rebar Cover - Top Face: Rebar Cover 1 <25 mm>
Other - Type Id: 814731; Family: V_TA Stål Facade Columns Type 4; Type: V_TA Stål Facade Columns; Family and Type: V_TA Stål Facade Columns Type 4: V_TA Stål Facade Columns
ePset_Simplebim - Assembly Level: Leaf
Pset_BuildingElementProxyCommon - Reference: V_TA Stål Facade Columns; sets with these values: 2
ePset_SimplebimBasicQuantities - Thickness (Simplebim): 20 mm
Name (V_TA Stål Facade Columns Type 4:V_TA Stål Facade Columns:...) | Area, largest surface, net (Simplebim) (m2) | Volume, net (Simplebim) (m3) | Height (Simplebim) (mm) | Length (Simplebim) (mm)
814869 | 0.0688088 | 0.00137618 | 308 | 337
815002 | 0.0728745 | 0.00145749 | 322 | 341
838913 | 0.0728745 | 0.00145749 | 322 | 341

# IfcBuildingElementProxy: V_TA Stål Facade Columns Type 5:V_TA Stål Facade Columns, V_TA Stål Facade Columns Type 5:V_TA Stål Facade Columns:810007
In: XX - C +15,37 TA E2
Type - Material: <Unnamed>
Type - Other - Category: Structural Framing; Family Name: V_TA Stål Facade Columns Type 5
Type - Constraints - Default Elevation: 1219.2 mm
Type - Identity Data - Type Name: V_TA Stål Facade Columns; Workset: Family : Structural Framing : V_TA Stål Facade Columns Type 5
Type - Structural - Section Shape: 0
Phasing - Phase Created: Som Bygget
Constraints - Host: System Panel : Glazed-generic; Schedule Level: XX - C +15,37 TA E2; Level: XX - C +15,37 TA E2
Identity Data - TA Workset: yes; Workset: XTA Terminal A
Structural - Rebar Cover - Bottom Face: Rebar Cover 1 <25 mm>; Rebar Cover - Other Faces: Rebar Cover 1 <25 mm>; Rebar Cover - Top Face: Rebar Cover 1 <25 mm>
ePset_SimplebimBasicQuantities - Volume, net (Simplebim): 0.00138262 m3; Area, largest surface, net (Simplebim): 0.069131 m2; Thickness (Simplebim): 20 mm; Height (Simplebim): 309 mm; Length (Simplebim): 337 mm
ePset_Simplebim - Assembly Level: Leaf
Other - Family: V_TA Stål Facade Columns Type 5; Family and Type: V_TA Stål Facade Columns Type 5: V_TA Stål Facade Columns; Type: V_TA Stål Facade Columns; Type Id: 804744
ePset_LocationTool - Splitting: RESULT
Pset_BuildingElementProxyCommon - Reference: V_TA Stål Facade Columns; sets with these values: 2

# IfcRoof: V_TA Roof (4):Standard, V_TA Roof (4):Standard:419392
In: XX - C +18,10 TB Tak 1
Material: Default Roof
Phasing - Phase Created: Som Bygget
Pset_QuantityTakeOff - Reference: Standard
Identity Data - TA Workset: yes; Workset: XTA Terminal A
Pset_RoofCommon - IsExternal: yes; TotalArea: 13.7415 m2; Reference: Standard
Other - Family: V_TA Roof (4); Family and Type: V_TA Roof (4): Standard; Type Id: 419390; Category: Roofs; Type: Standard
Dimensions - Volume: 1324.99 m3; Area: 13.7415 m2
ePset_SimplebimBasicQuantities - Volume, net (Simplebim): 1324.99 m3; Height: 1796 mm; Width: 9880 mm; Length: 96423 mm
ePset_Simplebim - Assembly Level: Topmost
Constraints - Room Bounding: yes; Elevation from Level: 0 mm; Moves With Nearby Elements: no

# IfcSlab: Floor:NSW Generic 350 mm, Floor:NSW Generic 350 mm:328248
In: XX - C +15,37 TA E2
Type - PredefinedType: FLOOR; Material: Værnes_Aluminium 70 mm, _NSW Betong 280 mm
Type - Other - Category: Floors; Family Name: Floor
Type - Construction - Default Thickness: 350 mm; Function: Interior
Type - Graphics - Coarse Scale Fill Color: 0
Type - Identity Data - Type Name: NSW Generic 350 mm; Workset: Floor Types
Type - Materials and Finishes - Structural Material: _NSW Betong
Type - Text - Gulv Code: -
Type - Analytical Properties - Absorptance: 0.1; Roughness: 1
Type - Pset_SlabCommon - IsExternal: no
Structural - Structural: no
Other - Family and Type: Floor: NSW Generic 350 mm; Type: NSW Generic 350 mm; Family: Floor; Type Id: 11533893
Pset_QuantityTakeOff - Reference: NSW Generic 350 mm; sets with these values: 2
Phasing - Phase Created: Som Bygget
ePset_Simplebim - Assembly Level: Leaf
ePset_SimplebimBasicQuantities - Area, sides, net (Simplebim): 15.2803 m2; Area, largest surface, net (Simplebim): 118.026 m2; Area, top, net (Simplebim): 118.026 m2; Perimeter (Simplebim): 43658.1 mm; Thickness (Simplebim): 350 mm; Volume, net (Simplebim): 41.3091 m3
ePset_LocationTool - Splitting: RESULT
Constraints - Related to Mass: no; Room Bounding: yes; Level: XX - C +15,37 TA E2
Identity Data - Has Association: no; TA Workset: yes; Workset: XTA Terminal A
Pset_SlabCommon - Reference: NSW Generic 350 mm; LoadBearing: no

# IfcSlab: V_TA Roof (4):Standard, V_TA Roof (4):Standard:419392:1
In: XX - C +18,10 TB Tak 1
Type - PredefinedType: ROOF
Type - Other - Category: Roofs; Family Name: V_TA Roof (4)
Type - Identity Data - Type Name: Standard; Workset: XTA Terminal A
Type - Pset_SlabCommon - IsExternal: yes
Type - Materials and Finishes - Roof 1: Default Roof
Pset_QuantityTakeOff - Reference: Standard; sets with these values: 2
Pset_SlabCommon - Reference: Standard
ePset_Simplebim - Assembly Level: Leaf
ePset_SimplebimBasicQuantities - Area, largest surface, net (Simplebim): 115.398 m2; Area, sides, net (Simplebim): 62.5816 m2; Volume, net (Simplebim): 148.888 m3; Thickness (Simplebim): 1321.81 mm; Perimeter (Simplebim): 47345.3 mm; Area, top, net (Simplebim): 113.386 m2
ePset_LocationTool - Splitting: RESULT

# IfcWall: Basic Wall:242_Værnes Innervegg 38_150mm, Basic Wall:242_Værnes Innervegg 38_150mm:1056977
In: XX - C +15,37 TA E2
Type - PredefinedType: STANDARD; Material: Værnes_Glass 05_Silketrykket 10 mm, Værnes_Malt 2 mm, Værnes_Gipsplate 13 mm, Værnes_Stålstender 150 mm, Værnes_Gipsplate 13 mm, Værnes_Malt 2 mm
Type - Other - Category: Walls; Family Name: Basic Wall
Type - Construction - Function: Interior; Width: 190 mm; Wrapping at Inserts: Do not wrap
Type - Graphics - Coarse Scale Fill Color: 0; Coarse Scale Fill Pattern: vertikale felter 1200mm bredde
Type - Identity Data - Type Name: 242_Værnes Innervegg 38_150mm; Workset: Wall Types
Type - Materials and Finishes - Structural Material: Værnes_Stålstender
Type - Text - Core Kode: 150G-G M0; Vegg Kode: IV38
Type - Analytical Properties - Roughness: 1; Absorptance: 0.1
Type - Pset_WallCommon - IsExternal: no
Cross-Section Definition - Cross-Section: Vertical
Phasing - Phase Created: Som Bygget
Identity Data - Comments: Overflater på del av IV38 se ENVA-A-TA-E2-270-J-231; TA Workset: yes; E203 TETT BYGG: no; E204 INNVENDIGE: yes; Workset: XTA Terminal A
Structural - Structural Usage: Non-bearing; Structural: no
ePset_SimplebimBasicQuantities - Volume, net (Simplebim): 5.98044 m3; Area, side, net, smaller (Simplebim): 32.0427 m2; Area, side, gross, smaller (Simplebim): 32.0427 m2; Area, side, gross, average (Simplebim): 32.0427 m2; Area, side, net, average (Simplebim): 32.0427 m2; Area, side, gross, larger (Simplebim): 32.0427 m2; Area, largest surface, net (Simplebim): 32.0427 m2; Area, side, net, larger (Simplebim): 32.0427 m2; Area, side, gross, AABB (Simplebim): 32.0396 m2; Thickness (Simplebim): 190 mm; Height (Simplebim): 2678 mm; Length (Simplebim): 11964 mm
Other - Type: 242_Værnes Innervegg 38_150mm; Family: Basic Wall; Family and Type: Basic Wall: 242_Værnes Innervegg 38_150mm; Type Id: 7072229
Pset_WallCommon - Reference: 242_Værnes Innervegg 38_150mm; LoadBearing: no; ExtendToStructure: yes
Pset_ReinforcementBarPitchOfWall - Reference: 242_Værnes Innervegg 38_150mm; sets with these values: 2
ePset_Simplebim - Assembly Level: Leaf
ePset_LocationTool - Splitting: RESULT
Text - Code: TA E2
Constraints - Top Constraint: Up to level: XX - C +18,62; Location Line: Finish Face: Exterior; Related to Mass: no; Room Bounding: yes; Base is Attached: no; Top is Attached: yes; Base Constraint: XX - C +15,37 TA E2

# IfcWall: Basic Wall:V_Existing 150mm, Basic Wall:V_Existing 150mm:985468
In: XX - C +15,37 TA E2
Type - PredefinedType: STANDARD; Material: Existing - Bridget key 150 mm
Type - Other - Category: Walls; Family Name: Basic Wall
Type - Construction - Function: Exterior; Width: 150 mm; Wrapping at Inserts: Do not wrap
Type - Graphics - Coarse Scale Fill Color: 0
Type - Identity Data - Type Name: V_Existing 150mm; Workset: Wall Types
Type - Materials and Finishes - Structural Material: Existing - Bridget key
Type - Text - Core Kode: EKS
Type - Analytical Properties - Roughness: 1; Absorptance: 0.1
Type - Pset_WallCommon - IsExternal: yes
Cross-Section Definition - Cross-Section: Vertical
Phasing - Phase Created: Som Bygget
Other - Type: V_Existing 150mm; Family: Basic Wall; Type Id: 4520733; Family and Type: Basic Wall: V_Existing 150mm
Structural - Structural Usage: Non-bearing; Structural: no
ePset_LocationTool - Splitting: RESULT
Pset_WallCommon - Reference: V_Existing 150mm; LoadBearing: no; ExtendToStructure: yes
ePset_SimplebimBasicQuantities - Volume, net (Simplebim): 4.80641 m3; Area, side, net, larger (Simplebim): 32.0427 m2; Area, side, gross, smaller (Simplebim): 32.0427 m2; Area, side, net, smaller (Simplebim): 32.0427 m2; Area, largest surface, net (Simplebim): 32.0427 m2; Area, side, gross, larger (Simplebim): 32.0427 m2; Area, side, net, average (Simplebim): 32.0427 m2; Area, side, gross, average (Simplebim): 32.0427 m2; Area, side, gross, AABB (Simplebim): 32.0396 m2; Thickness (Simplebim): 150 mm; Height (Simplebim): 2678 mm; Length (Simplebim): 11964 mm
Constraints - Location Line: Finish Face: Exterior; Related to Mass: no; Room Bounding: yes; Base is Attached: no; Top is Attached: yes; Base Constraint: XX - C +15,37 TA E2
ePset_Simplebim - Assembly Level: Leaf
Text - Code: TA E2 exist
Pset_ReinforcementBarPitchOfWall - Reference: V_Existing 150mm; sets with these values: 2
Identity Data - Workset: XTA Terminal A

# IfcWallStandardCase: Basic Wall:V_Existing 100mm, Basic Wall:V_Existing 100mm:1003670
In: XX - C +15,37 TA E2
Type - PredefinedType: STANDARD; Material: Existing - Bridget key 100 mm
Type - Other - Category: Walls; Family Name: Basic Wall
Type - Construction - Function: Interior; Width: 100 mm; Wrapping at Inserts: Both
Type - Graphics - Coarse Scale Fill Color: 0
Type - Identity Data - Type Name: V_Existing 100mm; Workset: Wall Types
Type - Materials and Finishes - Structural Material: Existing - Bridget key
Type - Text - Core Kode: EKS; Vegg Kode: EKS
Type - Analytical Properties - Roughness: 1; Absorptance: 0.1
Type - Pset_WallCommon - IsExternal: no
Pset_QuantityTakeOff - Reference: V_Existing 100mm; sets with these values: 2
Dimensions - Volume: 2.54753 m3; Length: 9737.2 mm; Area: 25.4753 m2
Cross-Section Definition - Cross-Section: Vertical
Phasing - Phase Created: Som Bygget
Structural - Structural Usage: Non-bearing; Structural: no
Identity Data - TA Workset: yes; Workset: XTA Terminal A
Pset_WallCommon - Reference: V_Existing 100mm; LoadBearing: no; ExtendToStructure: no
ePset_LocationTool - Splitting: ORIGINAL
ePset_SimplebimBasicQuantities - Volume, net (Simplebim): 2.54753 m3; Length (Simplebim): 9662.2 mm; Height (Simplebim): 2636.6 mm; Area, side, gross, larger (Simplebim): 25.4753 m2; Area, side, net, larger (Simplebim): 25.4753 m2; Area, side, gross, smaller (Simplebim): 25.4753 m2; Area, side, net, smaller (Simplebim): 25.4753 m2; Area, largest surface, net (Simplebim): 25.4753 m2; Area, side, net, average (Simplebim): 25.4753 m2; Area, side, gross, average (Simplebim): 25.4753 m2; Area, side, gross, AABB (Simplebim): 25.4753 m2; Thickness (Simplebim): 100 mm
Other - Type: V_Existing 100mm; Family: Basic Wall; Type Id: 204692; Family and Type: Basic Wall: V_Existing 100mm
ePset_Simplebim - Assembly Level: Leaf
Constraints - Location Line: Finish Face: Exterior; Unconnected Height: 2636.6 mm; Base Offset: 0 mm; Related to Mass: no; Room Bounding: yes; Base is Attached: no; Top is Attached: no; Top Offset: 0 mm; Base Extension Distance: 0 mm; Top Extension Distance: 0 mm; Base Constraint: XX - C +15,37 TA E2
